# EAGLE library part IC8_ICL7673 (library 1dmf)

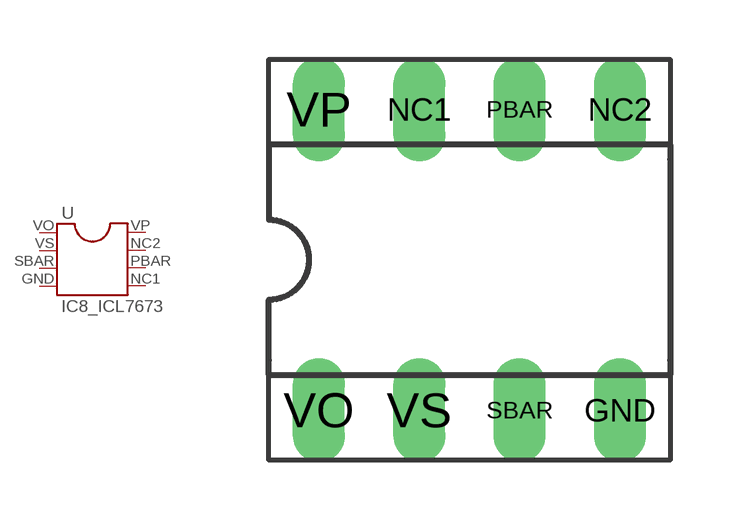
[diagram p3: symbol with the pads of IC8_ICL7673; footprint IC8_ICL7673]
Designator prefix -

## IC8_ICL76731  [IC8_ICL7673]
GND  4  pas
NC1  5  pas
NC2  7  pas
PBAR  6  pas
SBAR  3  pas
VO  1  pas
VP  8  pas
VS  2  pas

## Footprint IC8_ICL7673 (pad centres in mm)
drill 0.813 long: GND 3.81,-3.81; NC1 -1.27,3.81; NC2 3.81,3.81; PBAR 1.27,3.81; SBAR 1.27,-3.81; VO -3.81,-3.81; VP -3.81,3.81; VS -1.27,-3.81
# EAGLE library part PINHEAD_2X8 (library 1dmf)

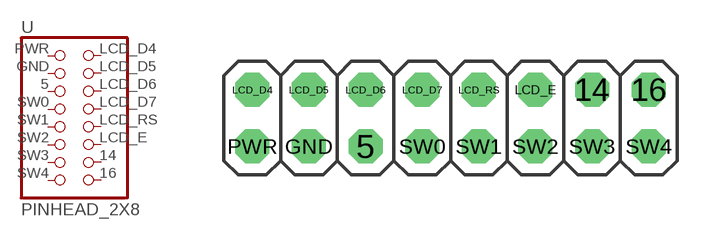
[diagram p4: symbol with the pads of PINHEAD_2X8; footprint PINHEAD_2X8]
Designator prefix -

## PINHEAD_2X81  [PINHEAD_2X8]
5  5  pas
14  14  pas
16  16  pas
GND  3  pas
LCD_D4  2  pas
LCD_D5  4  pas
LCD_D6  6  pas
LCD_D7  8  pas
LCD_E  12  pas
LCD_RS  10  pas
PWR  1  pas
SW0  7  pas
SW1  9  pas
SW2  11  pas
SW3  13  pas
SW4  15  pas

## Footprint PINHEAD_2X8 (pad centres in mm)
drill 1.016 octagon: 5 -3.81,-1.27; 14 6.35,1.27; 16 8.89,1.27; GND -6.35,-1.27; LCD_D4 -8.89,1.27; LCD_D5 -6.35,1.27; LCD_D6 -3.81,1.27; LCD_D7 -1.27,1.27; LCD_E 3.81,1.27; LCD_RS 1.27,1.27; PWR -8.89,-1.27; SW0 -1.27,-1.27; SW1 1.27,-1.27; SW2 3.81,-1.27; SW3 6.35,-1.27; SW4 8.89,-1.27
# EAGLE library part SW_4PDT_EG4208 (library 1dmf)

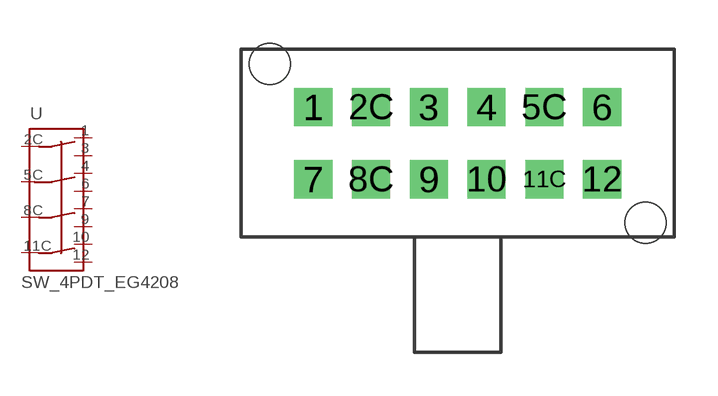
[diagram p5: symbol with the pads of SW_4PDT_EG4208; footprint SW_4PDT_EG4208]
Designator prefix -

## SW_4PDT_EG4208  [SW_4PDT_EG4208]
1  1  pas
2C  2  pas
3  3  pas
4  4  pas
5C  5  pas
6  6  pas
7  7  pas
8C  8  pas
9  9  pas
10  10  pas
11C  11  pas
12  12  pas

## Footprint SW_4PDT_EG4208 (pad centres in mm)
drill 0.813 square: 1 -5,1.25; 2C -3,1.25; 3 -1,1.25; 4 1,1.25; 5C 3,1.25; 6 5,1.25; 7 -5,-1.25; 8C -3,-1.25; 9 -1,-1.25; 10 1,-1.25; 11C 3,-1.25; 12 5,-1.25
hole 1.422 at 6.5,-2.75
hole 1.422 at -6.5,2.75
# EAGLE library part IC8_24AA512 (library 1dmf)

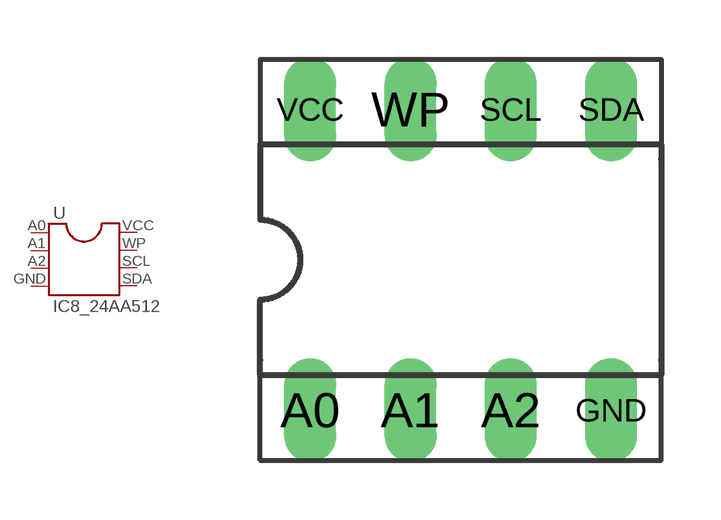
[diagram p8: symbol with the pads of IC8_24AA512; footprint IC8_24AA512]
Designator prefix -

## IC8_24AA512  [IC8_24AA512]
A0  1  pas
A1  2  pas
A2  3  pas
GND  4  pas
SCL  6  pas
SDA  5  pas
VCC  8  pas
WP  7  pas

## Footprint IC8_24AA512 (pad centres in mm)
drill 0.813 long: A0 -3.81,-3.81; A1 -1.27,-3.81; A2 1.27,-3.81; GND 3.81,-3.81; SCL 1.27,3.81; SDA 3.81,3.81; VCC -3.81,3.81; WP -1.27,3.81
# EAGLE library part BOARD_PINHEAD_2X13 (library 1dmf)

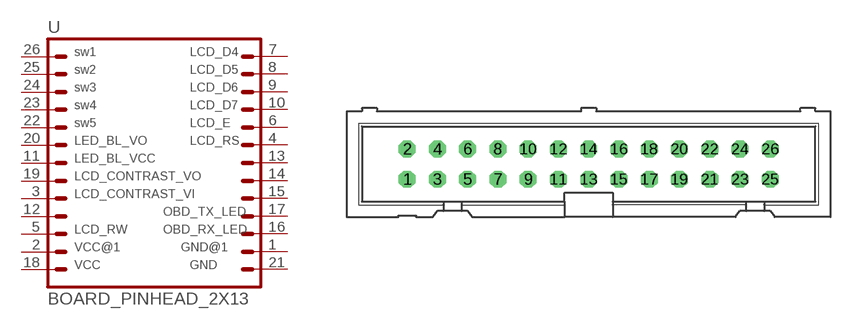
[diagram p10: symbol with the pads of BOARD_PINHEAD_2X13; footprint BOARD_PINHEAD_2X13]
Designator prefix -

## BOARD_PINHEAD_2X13  [BOARD_PINHEAD_2X13]
1  GND  pas
2  VCC  pas
3  LCD_CONTRAST_VI  pas
4  LCD_RS  pas
5  LCD_RW  pas
6  LCD_E  pas
7  LCD_D4  pas
8  LCD_D5  pas
9  LCD_D6  pas
10  LCD_D7  pas
11  LED_BL_VCC  pas
12  12  pas
13  13  pas
14  14  pas
15  15  pas
16  OBD_RX_LED  pas
17  OBD_TX_LED  pas
18  VCC  pas
19  LCD_CONTRAST_VO  pas
20  LED_BL_VO  pas
21  GND  pas
22  SW5  pas
23  SW4  pas
24  SW3  pas
25  SW2  pas
26  SW1  pas

## Footprint BOARD_PINHEAD_2X13 (pad centres in mm)
drill 0.914 octagon: 1 -15.24,-1.27; 2 -15.24,1.27; 3 -12.7,-1.27; 4 -12.7,1.27; 5 -10.16,-1.27; 6 -10.16,1.27; 7 -7.62,-1.27; 8 -7.62,1.27; 9 -5.08,-1.27; 10 -5.08,1.27; 11 -2.54,-1.27; 12 -2.54,1.27; 13 0,-1.27; 14 0,1.27; 15 2.54,-1.27; 16 2.54,1.27; 17 5.08,-1.27; 18 5.08,1.27; 19 7.62,-1.27; 20 7.62,1.27; 21 10.16,-1.27; 22 10.16,1.27; 23 12.7,-1.27; 24 12.7,1.27; 25 15.24,-1.27; 26 15.24,1.27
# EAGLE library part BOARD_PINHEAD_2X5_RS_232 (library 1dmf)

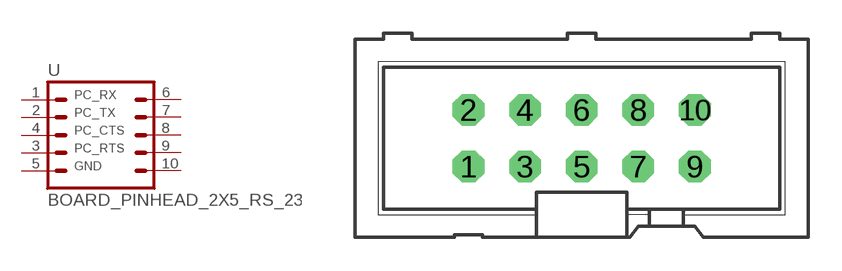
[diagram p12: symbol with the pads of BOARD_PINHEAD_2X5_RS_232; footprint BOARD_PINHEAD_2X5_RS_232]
Designator prefix -

## BOARD_PINHEAD_2X5_RS_232  [BOARD_PINHEAD_2X5_RS_232]
1  PC_RX  pas
2  PC_TX  pas
3  PC_RTS  pas
4  PC_CTS  pas
5  GND  pas
6  6  pas
7  7  pas
8  8  pas
9  9  pas
10  10  pas

## Footprint BOARD_PINHEAD_2X5_RS_232 (pad centres in mm)
drill 0.914 octagon: 1 -5.08,-1.27; 2 -5.08,1.27; 3 -2.54,-1.27; 4 -2.54,1.27; 5 0,-1.27; 6 0,1.27; 7 2.54,-1.27; 8 2.54,1.27; 9 5.08,-1.27; 10 5.08,1.27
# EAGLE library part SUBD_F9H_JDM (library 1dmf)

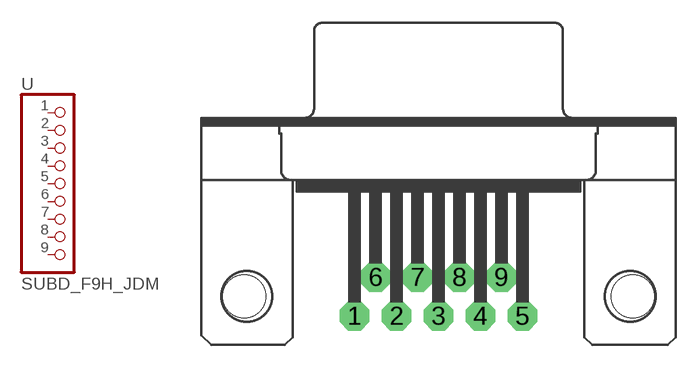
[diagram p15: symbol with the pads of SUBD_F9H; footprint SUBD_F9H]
Designator prefix -

## SUBD_F9H_JDM  [SUBD_F9H]
1  1  pas
2  2  pas
3  3  pas
4  4  pas
5  5  pas
6  6  pas
7  7  pas
8  8  pas
9  9  pas

## Footprint SUBD_F9H (pad centres in mm)
drill 1.016 pad 1.93 octagon: 1 -5.486,-7.62; 2 -2.743,-7.62; 3 0,-7.62; 4 2.743,-7.62; 5 5.486,-7.62; 6 -4.115,-5.08; 7 -1.372,-5.08; 8 1.372,-5.08; 9 4.115,-5.08
hole 2.8 at -12.7,-6.35
hole 2.8 at 12.7,-6.35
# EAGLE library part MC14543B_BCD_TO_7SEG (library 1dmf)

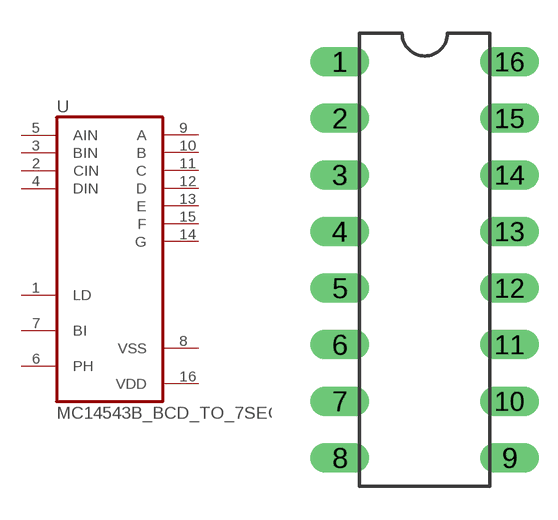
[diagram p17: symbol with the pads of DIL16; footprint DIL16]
Designator prefix -

## MC14543B_BCD_TO_7SEG  [DIL16]
1  LD
2  CIN
3  BIN
4  DIN
5  AIN
6  PH
7  BI
8  VSS  pwr
9  A
10  B
11  C
12  D
13  E
14  G
15  F
16  VDD  pwr

## Footprint DIL16 (pad centres in mm)
drill 0.813 long: 1 -3.81,7.62; 2 -3.81,5.08; 3 -3.81,2.54; 4 -3.81,0; 5 -3.81,-2.54; 6 -3.81,-5.08; 7 -3.81,-7.62; 8 -3.81,-10.16; 9 3.81,-10.16; 10 3.81,-7.62; 11 3.81,-5.08; 12 3.81,-2.54; 13 3.81,0; 14 3.81,2.54; 15 3.81,5.08; 16 3.81,7.62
